# Hand-written demonstration LEF for CadCraft's Chip design tests. Made-up numbers, no foundry's rules.
VERSION 5.8 ;
BUSBITCHARS "[]" ;
DIVIDERCHAR "/" ;
UNITS
  DATABASE MICRONS 1000 ;
END UNITS
MANUFACTURINGGRID 0.005 ;

LAYER poly
  TYPE MASTERSLICE ;
END poly

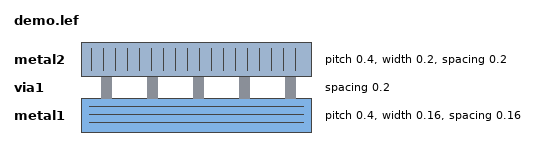
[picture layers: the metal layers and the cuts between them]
LAYER metal1
  TYPE ROUTING ;
  DIRECTION HORIZONTAL ;
  PITCH 0.4 ;
  WIDTH 0.16 ;
  SPACING 0.16 ;
  OFFSET 0.2 ;
  RESISTANCE RPERSQ 0.08 ;
END metal1

LAYER via1
  TYPE CUT ;
  SPACING 0.2 ;
END via1

LAYER metal2
  TYPE ROUTING ;
  DIRECTION VERTICAL ;
  PITCH 0.4 ;
  WIDTH 0.2 ;
  SPACING 0.2 ;
END metal2

VIA via12 DEFAULT
  LAYER metal1 ;
    RECT -0.1 -0.1 0.1 0.1 ;
  LAYER via1 ;
    RECT -0.07 -0.07 0.07 0.07 ;
  LAYER metal2 ;
    RECT -0.1 -0.1 0.1 0.1 ;
END via12

SITE core
  CLASS CORE ;
  SYMMETRY Y ;
  SIZE 0.4 BY 3.6 ;
END core

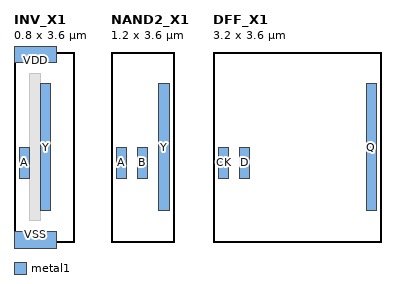
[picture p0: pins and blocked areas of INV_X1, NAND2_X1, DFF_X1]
MACRO INV_X1
  CLASS CORE ;
  ORIGIN 0 0 ;
  FOREIGN INV_X1 0 0 ;
  SIZE 0.8 BY 3.6 ;
  SYMMETRY X Y ;
  SITE core ;
  PIN A
    DIRECTION INPUT ;
    USE SIGNAL ;
    PORT
      LAYER metal1 ;
        RECT 0.1 1.2 0.3 1.8 ;
    END
  END A
  PIN Y
    DIRECTION OUTPUT ;
    USE SIGNAL ;
    PORT
      LAYER metal1 ;
        POLYGON 0.5 0.6 0.7 0.6 0.7 3.0 0.5 3.0 ;
    END
  END Y
  PIN VDD
    DIRECTION INOUT ;
    USE POWER ;
    SHAPE ABUTMENT ;
    PORT
      LAYER metal1 ;
        RECT 0 3.4 0.8 3.8 ;
    END
  END VDD
  PIN VSS
    DIRECTION INOUT ;
    USE GROUND ;
    PORT
      LAYER metal1 ;
        RECT 0 -0.2 0.8 0.2 ;
    END
  END VSS
  OBS
    LAYER metal1 ;
      RECT 0.3 0.4 0.5 3.2 ;
  END
END INV_X1

MACRO NAND2_X1
  CLASS CORE ;
  SIZE 1.2 BY 3.6 ;
  SITE core ;
  PIN A
    DIRECTION INPUT ;
    PORT
      LAYER metal1 ;
        RECT 0.1 1.2 0.3 1.8 ;
    END
  END A
  PIN B
    DIRECTION INPUT ;
    PORT
      LAYER metal1 ;
        RECT 0.5 1.2 0.7 1.8 ;
    END
  END B
  PIN Y
    DIRECTION OUTPUT ;
    PORT
      LAYER metal1 ;
        RECT 0.9 0.6 1.1 3.0 ;
    END
  END Y
END NAND2_X1

MACRO DFF_X1
  CLASS CORE ;
  SIZE 3.2 BY 3.6 ;
  SITE core ;
  PIN CK DIRECTION INPUT ; PORT LAYER metal1 ; RECT 0.1 1.2 0.3 1.8 ; END END CK
  PIN D DIRECTION INPUT ; PORT LAYER metal1 ; RECT 0.5 1.2 0.7 1.8 ; END END D
  PIN Q DIRECTION OUTPUT ; PORT LAYER metal1 ; RECT 2.9 0.6 3.1 3.0 ; END END Q
END DFF_X1

END LIBRARY
